One B-rep face of a CAD part: STEP entity #1321.
In plain terms, the planar face has unit normal (-1, 0, 0).
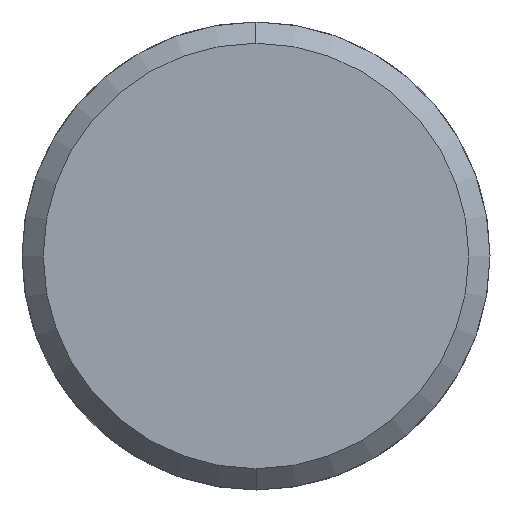
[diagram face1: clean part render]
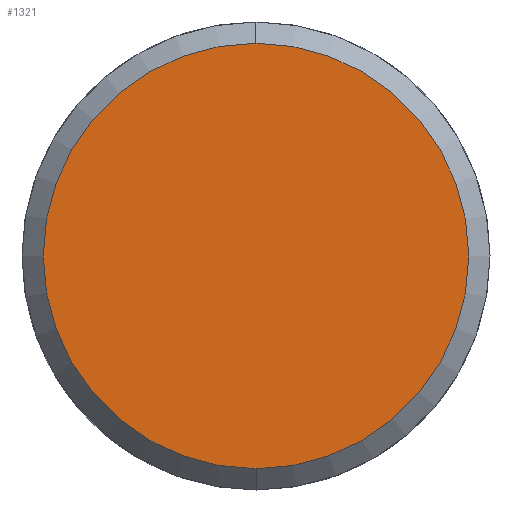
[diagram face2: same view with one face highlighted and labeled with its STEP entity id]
Its self-contained STEP definition (entity closure, numbers rounded to 3 decimals):
#1253=CARTESIAN_POINT('Vertex',(-5.,0.,-10.)) ;
#1256=CARTESIAN_POINT('Axis2P3D Location',(-5.,0.,0.)) ;
#1260=CARTESIAN_POINT('Vertex',(-5.,10.,0.)) ;
#1263=CARTESIAN_POINT('Axis2P3D Location',(-5.,0.,0.)) ;
#1267=CARTESIAN_POINT('Vertex',(-5.,0.,10.)) ;
#1289=CARTESIAN_POINT('Axis2P3D Location',(-5.,0.,0.)) ;
#1293=CARTESIAN_POINT('Vertex',(-5.,-10.,0.)) ;
#1296=CARTESIAN_POINT('Axis2P3D Location',(-5.,0.,0.)) ;
#1310=CARTESIAN_POINT('Axis2P3D Location',(-5.,0.,0.)) ;
#1257=DIRECTION('Axis2P3D Direction',(1.,0.,-0.)) ;
#1264=DIRECTION('Axis2P3D Direction',(1.,0.,-0.)) ;
#1290=DIRECTION('Axis2P3D Direction',(1.,0.,-0.)) ;
#1297=DIRECTION('Axis2P3D Direction',(1.,0.,-0.)) ;
#1311=DIRECTION('Axis2P3D Direction',(1.,0.,-0.)) ;
#1312=DIRECTION('Axis2P3D XDirection',(-0.,0.,-1.)) ;
#1258=AXIS2_PLACEMENT_3D('Circle Axis2P3D',#1256,#1257,$) ;
#1265=AXIS2_PLACEMENT_3D('Circle Axis2P3D',#1263,#1264,$) ;
#1291=AXIS2_PLACEMENT_3D('Circle Axis2P3D',#1289,#1290,$) ;
#1298=AXIS2_PLACEMENT_3D('Circle Axis2P3D',#1296,#1297,$) ;
#1313=AXIS2_PLACEMENT_3D('Plane Axis2P3D',#1310,#1311,#1312) ;
#1316=ORIENTED_EDGE('',*,*,#1262,.F.) ;
#1317=ORIENTED_EDGE('',*,*,#1300,.F.) ;
#1318=ORIENTED_EDGE('',*,*,#1295,.F.) ;
#1319=ORIENTED_EDGE('',*,*,#1269,.F.) ;
#1321=ADVANCED_FACE('351-12X26X100',(#1320),#1314,.F.) ;
#1259=CIRCLE('generated circle',#1258,10.) ;
#1266=CIRCLE('generated circle',#1265,10.) ;
#1292=CIRCLE('generated circle',#1291,10.) ;
#1299=CIRCLE('generated circle',#1298,10.) ;
#1262=EDGE_CURVE('',#1254,#1261,#1259,.T.) ;
#1269=EDGE_CURVE('',#1261,#1268,#1266,.T.) ;
#1295=EDGE_CURVE('',#1268,#1294,#1292,.T.) ;
#1300=EDGE_CURVE('',#1294,#1254,#1299,.T.) ;
#1315=EDGE_LOOP('',(#1316,#1317,#1318,#1319)) ;
#1320=FACE_OUTER_BOUND('',#1315,.T.) ;
#1314=PLANE('Plane',#1313) ;
#1254=VERTEX_POINT('',#1253) ;
#1261=VERTEX_POINT('',#1260) ;
#1268=VERTEX_POINT('',#1267) ;
#1294=VERTEX_POINT('',#1293) ;
